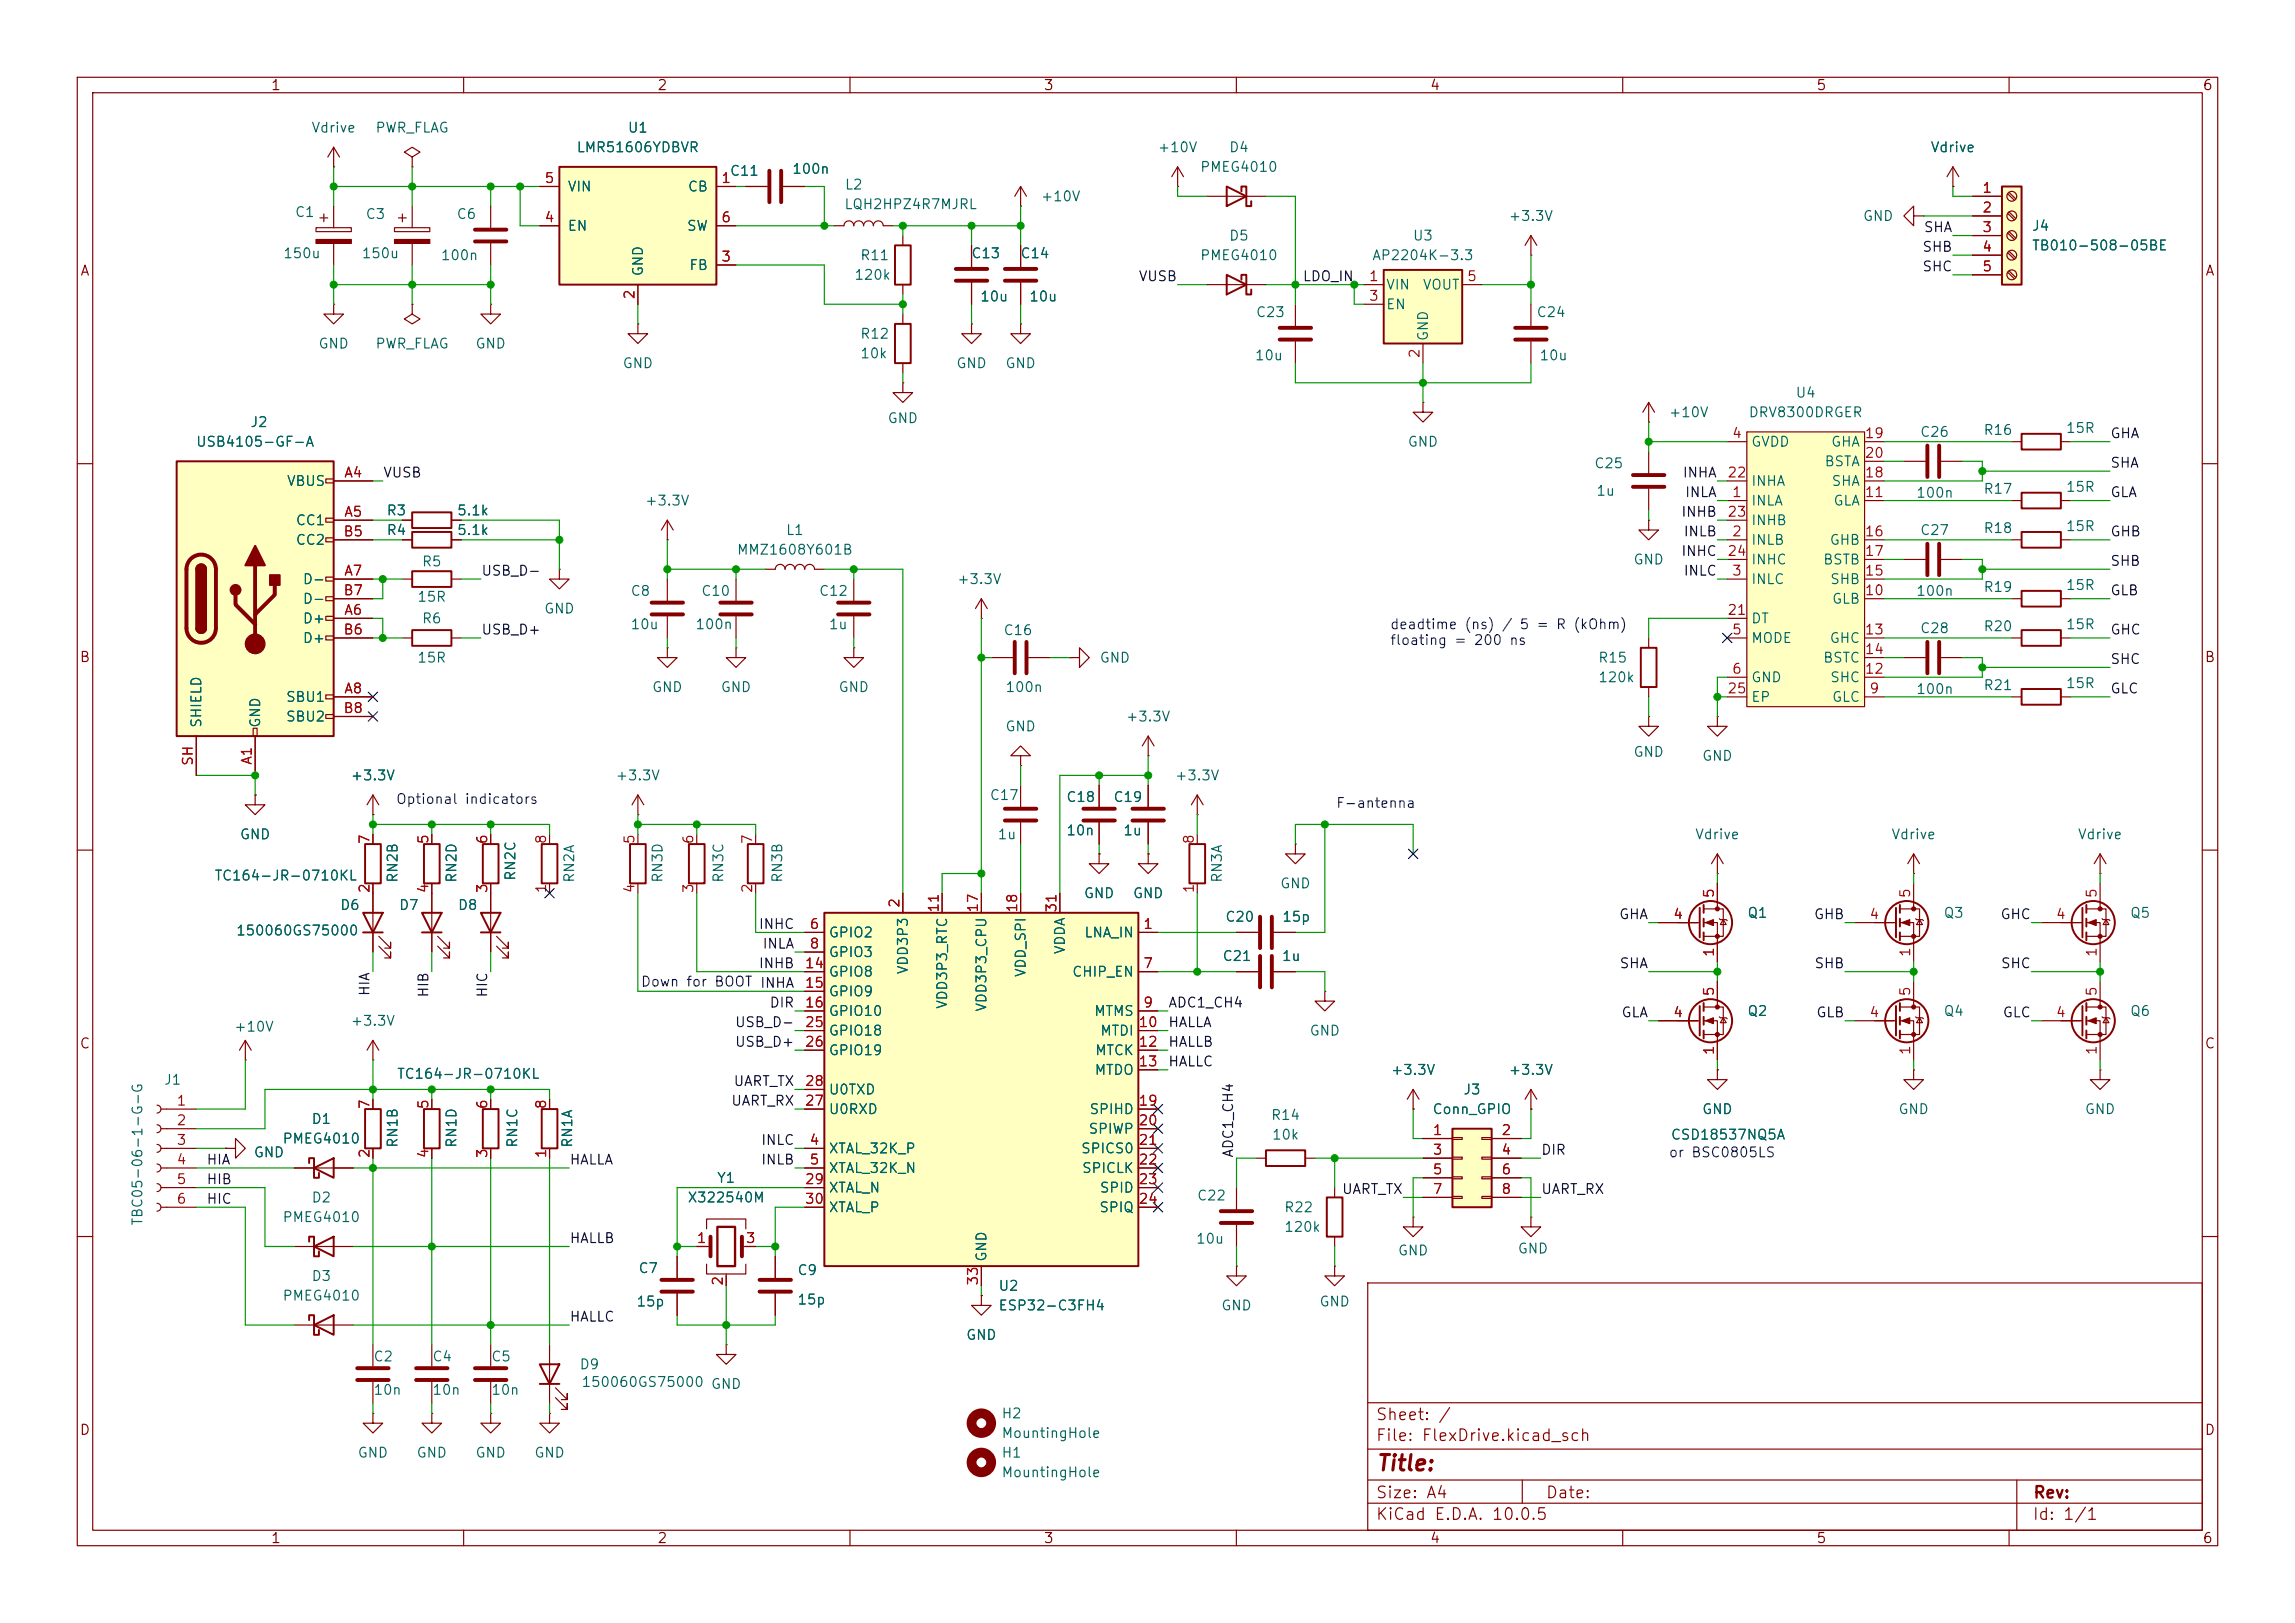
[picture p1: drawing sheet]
<svg xmlns="http://www.w3.org/2000/svg" width="297mm" height="210mm" viewBox="0 0 297 210" stroke-linecap="round" stroke-linejoin="round" font-family="sans-serif">
<defs><g id="words">
<text font-size="2" fill="#840000" x="178" y="190.8">Title:</text>
<g font-size="1.5" fill="#840000">
<text x="178" y="184.1">Sheet: /</text>
<text x="178" y="186.8">File: FlexDrive.kicad_sch</text>
<text x="178" y="197">KiCad E.D.A. 10.0.5</text>
<text x="178" y="194.2">Size: A4</text>
<text x="200" y="194.2">Date:</text>
<text x="263" y="197">Id: 1/1</text>
<text x="263" y="194.2">Rev:</text>
</g>
<g font-size="1.3" fill="#840000">
<text x="35" y="12">1</text>
<text x="85" y="12">2</text>
<text x="135" y="12">3</text>
<text x="185" y="12">4</text>
<text x="235" y="12">5</text>
<text x="285" y="12">6</text>
<text x="10.3" y="36">A</text>
<text x="285.3" y="36">A</text>
<text x="10.2" y="86">B</text>
<text x="285.2" y="86">B</text>
<text x="10.2" y="136">C</text>
<text x="285.2" y="136">C</text>
<text x="10.2" y="186">D</text>
<text x="285.2" y="186">D</text>
<text x="35" y="200">1</text>
<text x="85" y="200">2</text>
<text x="135" y="200">3</text>
<text x="185" y="200">4</text>
<text x="235" y="200">5</text>
<text x="285" y="200">6</text>
</g>
<g font-size="1.3" fill="#006464">
<text x="40.2" y="17.5">Vdrive</text>
<text x="48.5" y="17.5">PWR_FLAG</text>
<text x="81.2" y="17.5">U1</text>
<text x="74.5" y="20">LMR51606YDBVR</text>
<text x="94.4" y="23.1">C11</text>
<text x="102.4" y="22.8">100n</text>
<text x="149.7" y="20">+10V</text>
<text x="155.2" y="22.6">PMEG4010</text>
<text x="159" y="20">D4</text>
<text x="249.8" y="20">Vdrive</text>
<text x="38.1" y="28.4">C1</text>
<text x="47.2" y="28.6">C3</text>
<text x="59" y="28.6">C6</text>
<text x="73.4" y="25.1">VIN</text>
<text x="88.9" y="25.1">CB</text>
<text x="109.2" y="27.4">LQH2HPZ4R7MJRL</text>
<text x="109.2" y="24.8">L2</text>
<text x="134.6" y="26.4">+10V</text>
<text x="195.2" y="28.9">+3.3V</text>
<text x="241" y="28.9">GND</text>
<text x="36.6" y="33.7">150u</text>
<text x="46.7" y="33.7">150u</text>
<text x="57" y="34">100n</text>
<text x="73.4" y="30.2">EN</text>
<text x="83.5" y="35.8" transform="rotate(-90 83.5 35.8)">GND</text>
<text x="88.8" y="30.2">SW</text>
<text x="89.1" y="35.3">FB</text>
<text x="111.2" y="34">R11</text>
<text x="125.6" y="33.7">C13</text>
<text x="132" y="33.7">C14</text>
<text x="155.2" y="34">PMEG4010</text>
<text x="159" y="31.4">D5</text>
<text x="177.5" y="34">AP2204K-3.3</text>
<text x="182.8" y="31.4">U3</text>
<text x="262.9" y="30.2">J4</text>
<text x="262.9" y="32.7">TB010-508-05BE</text>
<text x="110.5" y="36.5">120k</text>
<text x="126.7" y="39.3">10u</text>
<text x="133.1" y="39.3">10u</text>
<text x="162.4" y="41.3">C23</text>
<text x="179.3" y="37.8">VIN</text>
<text x="179.3" y="40.3">EN</text>
<text x="184" y="37.8">VOUT</text>
<text x="198.8" y="41.3">C24</text>
<text x="41.1" y="45.4">GND</text>
<text x="48.5" y="45.4">PWR_FLAG</text>
<text x="61.4" y="45.4">GND</text>
<text x="80.5" y="48">GND</text>
<text x="111.2" y="44.1">R12</text>
<text x="111.2" y="46.7">10k</text>
<text x="123.7" y="48">GND</text>
<text x="130" y="48">GND</text>
<text x="162.3" y="46.9">10u</text>
<text x="185.1" y="44.2" transform="rotate(-90 185.1 44.2)">GND</text>
<text x="199.1" y="46.9">10u</text>
<text x="232.3" y="51.8">U4</text>
<text x="25.3" y="58.1">USB4105-GF-A</text>
<text x="32.3" y="55.6">J2</text>
<text x="114.8" y="55.1">GND</text>
<text x="182.1" y="58.1">GND</text>
<text x="215.9" y="54.3">+10V</text>
<text x="226.2" y="54.3">DRV8300DRGER</text>
<text x="226.5" y="58.1">GVDD</text>
<text x="236.9" y="58.1">GHA</text>
<text x="248.4" y="56.8">C26</text>
<text x="256.6" y="56.6">R16</text>
<text x="267.3" y="56.3">15R</text>
<text x="37" y="63.2">VBUS</text>
<text x="83.4" y="65.7">+3.3V</text>
<text x="206.2" y="60.9">C25</text>
<text x="206.5" y="64.5">1u</text>
<text x="226.5" y="65.7">INLA</text>
<text x="226.5" y="63.2">INHA</text>
<text x="236" y="60.7">BSTA</text>
<text x="236.9" y="63.2">SHA</text>
<text x="237.2" y="65.7">GLA</text>
<text x="247.9" y="64.7">100n</text>
<text x="256.6" y="64.2">R17</text>
<text x="267.3" y="64">15R</text>
<text x="38.2" y="68.3">CC1</text>
<text x="38.2" y="70.8">CC2</text>
<text x="49.9" y="69.5">R4</text>
<text x="49.9" y="67">R3</text>
<text x="59.1" y="69.5">5.1k</text>
<text x="59.1" y="67">5.1k</text>
<text x="101.6" y="69.5">L1</text>
<text x="226.5" y="70.8">INLB</text>
<text x="226.5" y="68.3">INHB</text>
<text x="236.7" y="70.8">GHB</text>
<text x="248.4" y="69.5">C27</text>
<text x="256.6" y="69.3">R18</text>
<text x="267.3" y="69">15R</text>
<text x="39.1" y="75.9">D-</text>
<text x="54.5" y="73.6">R5</text>
<text x="81.5" y="77.4">C8</text>
<text x="90.7" y="77.4">C10</text>
<text x="95.3" y="72.1">MMZ1608Y601B</text>
<text x="105.9" y="77.4">C12</text>
<text x="123.8" y="75.9">+3.3V</text>
<text x="211.3" y="73.4">GND</text>
<text x="226.5" y="75.9">INLC</text>
<text x="226.5" y="73.4">INHC</text>
<text x="235.8" y="73.4">BSTB</text>
<text x="236.8" y="75.9">SHB</text>
<text x="247.9" y="77.4">100n</text>
<text x="256.6" y="76.9">R19</text>
<text x="267.3" y="76.7">15R</text>
<text x="39.1" y="81">D+</text>
<text x="39.1" y="83.5">D+</text>
<text x="39.1" y="78.4">D-</text>
<text x="53.9" y="78.2">15R</text>
<text x="54.5" y="81">R6</text>
<text x="70.3" y="79.7">GND</text>
<text x="81.5" y="81.7">10u</text>
<text x="89.9" y="81.7">100n</text>
<text x="107.2" y="81.7">1u</text>
<text x="129.8" y="82.5">C16</text>
<text x="226.5" y="83.5">MODE</text>
<text x="226.5" y="81">DT</text>
<text x="236.7" y="83.5">GHC</text>
<text x="237" y="78.4">GLB</text>
<text x="248.4" y="82.2">C28</text>
<text x="256.6" y="82">R20</text>
<text x="267.3" y="81.7">15R</text>
<text x="53.9" y="86.1">15R</text>
<text x="84.3" y="89.9">GND</text>
<text x="93.2" y="89.9">GND</text>
<text x="108.4" y="89.9">GND</text>
<text x="130" y="89.9">100n</text>
<text x="142.2" y="86.1">GND</text>
<text x="206.7" y="86.1">R15</text>
<text x="206.7" y="88.6">120k</text>
<text x="226.5" y="88.6">GND</text>
<text x="235.8" y="86.1">BSTC</text>
<text x="236.8" y="88.6">SHC</text>
<text x="256.6" y="89.6">R21</text>
<text x="267.3" y="89.4">15R</text>
<text x="26.4" y="94.3" transform="rotate(-90 26.4 94.3)">SHIELD</text>
<text x="34" y="94.3" transform="rotate(-90 34 94.3)">GND</text>
<text x="36.9" y="91.1">SBU1</text>
<text x="36.9" y="93.7">SBU2</text>
<text x="130" y="94.9">GND</text>
<text x="145.6" y="93.7">+3.3V</text>
<text x="226.5" y="91.1">EP</text>
<text x="237" y="91.1">GLC</text>
<text x="247.9" y="90.1">100n</text>
<text x="45.3" y="101.3">+3.3V</text>
<text x="79.6" y="101.3">+3.3V</text>
<text x="152" y="101.3">+3.3V</text>
<text x="211.3" y="98.2">GND</text>
<text x="220.2" y="98.8">GND</text>
<text x="128" y="103.8">C17</text>
<text x="137.9" y="104.1">C18</text>
<text x="144" y="104.1">C19</text>
<text x="31" y="108.9">GND</text>
<text x="129" y="108.9">1u</text>
<text x="137.9" y="108.4">10n</text>
<text x="145.3" y="108.4">1u</text>
<text x="219.3" y="108.9">Vdrive</text>
<text x="244.7" y="108.9">Vdrive</text>
<text x="268.8" y="108.9">Vdrive</text>
<text x="27.7" y="114.2">TC164-JR-0710KL</text>
<text x="43.9" y="118.1">D6</text>
<text x="51.5" y="118.1">D7</text>
<text x="51.8" y="114.3" transform="rotate(-90 51.8 114.3)">RN2B</text>
<text x="59.2" y="118.1">D8</text>
<text x="59.4" y="114.3" transform="rotate(-90 59.4 114.3)">RN2D</text>
<text x="67" y="114.1" transform="rotate(-90 67 114.1)">RN2C</text>
<text x="74.6" y="114.3" transform="rotate(-90 74.6 114.3)">RN2A</text>
<text x="86.1" y="114.3" transform="rotate(-90 86.1 114.3)">RN3D</text>
<text x="93.9" y="114.3" transform="rotate(-90 93.9 114.3)">RN3C</text>
<text x="101.5" y="114.3" transform="rotate(-90 101.5 114.3)">RN3B</text>
<text x="140.2" y="116.5">GND</text>
<text x="146.5" y="116.5">GND</text>
<text x="158.4" y="114.3" transform="rotate(-90 158.4 114.3)">RN3A</text>
<text x="158.5" y="119.6">C20</text>
<text x="165.6" y="115.3">GND</text>
<text x="165.8" y="119.6">15p</text>
<text x="226" y="119.1">Q1</text>
<text x="251.4" y="119.1">Q3</text>
<text x="275.6" y="119.1">Q5</text>
<text x="30.5" y="121.4">150060GS75000</text>
<text x="107.2" y="121.6">GPIO2</text>
<text x="107.2" y="124.2">GPIO3</text>
<text x="138.1" y="123.6" transform="rotate(-90 138.1 123.6)">VDDA</text>
<text x="140.2" y="121.6">LNA_IN</text>
<text x="158.1" y="124.7">C21</text>
<text x="165.8" y="124.7">1u</text>
<text x="107.2" y="126.7">GPIO8</text>
<text x="107.2" y="129.2">GPIO9</text>
<text x="107.2" y="131.8">GPIO10</text>
<text x="117.8" y="126.2" transform="rotate(-90 117.8 126.2)">VDD3P3</text>
<text x="122.9" y="130.6" transform="rotate(-90 122.9 130.6)">VDD3P3_RTC</text>
<text x="128" y="131" transform="rotate(-90 128 131)">VDD3P3_CPU</text>
<text x="133" y="126.5" transform="rotate(-90 133 126.5)">VDD_SPI</text>
<text x="138.7" y="126.7">CHIP_EN</text>
<text x="141.5" y="131.8">MTMS</text>
<text x="226" y="131.8">Q2</text>
<text x="251.4" y="131.8">Q4</text>
<text x="275.6" y="131.8">Q6</text>
<text x="30.2" y="133.8">+10V</text>
<text x="45.3" y="133">+3.3V</text>
<text x="107.2" y="134.3">GPIO18</text>
<text x="107.2" y="136.9">GPIO19</text>
<text x="141.6" y="136.9">MTCK</text>
<text x="142.3" y="134.3">MTDI</text>
<text x="169.4" y="134.3">GND</text>
<text x="21.1" y="140.7">J1</text>
<text x="51.3" y="139.9">TC164-JR-0710KL</text>
<text x="107.2" y="141.9">U0TXD</text>
<text x="141.6" y="139.4">MTDO</text>
<text x="179.9" y="139.4">+3.3V</text>
<text x="189.3" y="141.9">J3</text>
<text x="195.2" y="139.4">+3.3V</text>
<text x="36.5" y="148.3">PMEG4010</text>
<text x="40.2" y="145.7">D1</text>
<text x="51.8" y="148.6" transform="rotate(-90 51.8 148.6)">RN1B</text>
<text x="59.4" y="148.6" transform="rotate(-90 59.4 148.6)">RN1D</text>
<text x="67.3" y="148.6" transform="rotate(-90 67.3 148.6)">RN1C</text>
<text x="74.4" y="148.6" transform="rotate(-90 74.4 148.6)">RN1A</text>
<text x="107.2" y="149.6">XTAL_32K_P</text>
<text x="107.2" y="144.5">U0RXD</text>
<text x="139.8" y="149.6">SPICS0</text>
<text x="140.8" y="147">SPIWP</text>
<text x="140.9" y="144.5">SPIHD</text>
<text x="164.4" y="145.2">R14</text>
<text x="164.5" y="147.8">10k</text>
<text x="185.3" y="144.5">Conn_GPIO</text>
<text x="216.1" y="147.8">CSD18537NQ5A</text>
<text x="220.2" y="144.5">GND</text>
<text x="245.6" y="144.5">GND</text>
<text x="269.7" y="144.5">GND</text>
<text x="32.8" y="150.1">GND</text>
<text x="40.2" y="155.9">D2</text>
<text x="88.9" y="155.9">X322540M</text>
<text x="92.7" y="153.4">Y1</text>
<text x="107.2" y="152.1">XTAL_32K_N</text>
<text x="107.2" y="154.6">XTAL_N</text>
<text x="139.9" y="152.1">SPICLK</text>
<text x="142.2" y="154.6">SPID</text>
<text x="154.8" y="155.6">C22</text>
<text x="18.7" y="158.7" transform="rotate(-90 18.7 158.7)">TBC05-06-1-G-G</text>
<text x="36.5" y="158.4">PMEG4010</text>
<text x="107.2" y="157.2">XTAL_P</text>
<text x="142.2" y="157.2">SPIQ</text>
<text x="154.7" y="161.2">10u</text>
<text x="166.1" y="157.2">R22</text>
<text x="166.1" y="159.7">120k</text>
<text x="40.2" y="166.1">D3</text>
<text x="82.5" y="165">C7</text>
<text x="103.1" y="165.3">C9</text>
<text x="128" y="163.3" transform="rotate(-90 128 163.3)">GND</text>
<text x="129.1" y="167.3">U2</text>
<text x="180.8" y="162.8">GND</text>
<text x="196.3" y="162.5">GND</text>
<text x="36.5" y="168.6">PMEG4010</text>
<text x="82.3" y="169.4">15p</text>
<text x="103.1" y="169.1">15p</text>
<text x="124.9" y="173.7">GND</text>
<text x="129.1" y="169.9">ESP32-C3FH4</text>
<text x="158" y="169.9">GND</text>
<text x="170.7" y="169.4">GND</text>
<text x="48.2" y="176.5">C2</text>
<text x="55.9" y="176.5">C4</text>
<text x="63.5" y="176.5">C5</text>
<text x="74.9" y="177.5">D9</text>
<text x="75.2" y="179.8">150060GS75000 GND</text>
<text x="48.2" y="180.8">10n</text>
<text x="55.9" y="180.8">10n</text>
<text x="63.5" y="180.8">10n</text>
<text x="129.5" y="183.8">H2</text>
<text x="46.2" y="188.9">GND</text>
<text x="53.8" y="188.9">GND</text>
<text x="61.4" y="188.9">GND</text>
<text x="69.1" y="188.9">GND</text>
<text x="129.5" y="188.9">H1</text>
<text x="129.5" y="191.5">MountingHole</text>
<text x="129.5" y="186.4">MountingHole</text>
</g>
<g font-size="1.3" fill="#a90000">
<text x="70.4" y="24">5</text>
<text x="93.2" y="24">1</text>
<text x="70.4" y="29.1">4</text>
<text x="93.2" y="29.1">6</text>
<text x="256.4" y="25.3">1</text>
<text x="256.4" y="27.8">2</text>
<text x="93.2" y="34.2">3</text>
<text x="256.4" y="30.3">3</text>
<text x="256.4" y="32.9">4</text>
<text x="256.4" y="35.4">5</text>
<text x="82.4" y="38.8" transform="rotate(-90 82.4 38.8)">2</text>
<text x="177.1" y="36.7">1</text>
<text x="177.1" y="39.2">3</text>
<text x="189.8" y="36.7">5</text>
<text x="184" y="46.5" transform="rotate(-90 184 46.5)">2</text>
<text x="224.1" y="57">4</text>
<text x="241.2" y="57">19</text>
<text x="241.2" y="59.6">20</text>
<text x="44.4" y="62.1">A4</text>
<text x="223.5" y="62.1">22</text>
<text x="224.1" y="64.6">1</text>
<text x="241.2" y="64.6">11</text>
<text x="241.2" y="62.1">18</text>
<text x="44.4" y="69.7">B5</text>
<text x="44.4" y="67.2">A5</text>
<text x="223.5" y="67.2">23</text>
<text x="224.1" y="69.7">2</text>
<text x="241.2" y="69.7">16</text>
<text x="44.4" y="77.3">B7</text>
<text x="44.4" y="74.8">A7</text>
<text x="223.5" y="72.3">24</text>
<text x="224.1" y="74.8">3</text>
<text x="241.2" y="77.3">10</text>
<text x="241.2" y="74.8">15</text>
<text x="241.2" y="72.3">17</text>
<text x="44.4" y="82.4">B6</text>
<text x="44.4" y="79.9">A6</text>
<text x="223.5" y="79.9">21</text>
<text x="224.1" y="82.4">5</text>
<text x="241.2" y="82.4">13</text>
<text x="224.1" y="87.5">6</text>
<text x="241.2" y="87.5">12</text>
<text x="241.2" y="85">14</text>
<text x="44.4" y="92.6">B8</text>
<text x="44.4" y="90">A8</text>
<text x="223.5" y="90">25</text>
<text x="241.8" y="90">9</text>
<text x="25.3" y="99.2" transform="rotate(-90 25.3 99.2)">SH</text>
<text x="32.9" y="99.1" transform="rotate(-90 32.9 99.1)">A1</text>
<text x="48.1" y="109.3" transform="rotate(-90 48.1 109.3)">7</text>
<text x="55.7" y="109.3" transform="rotate(-90 55.7 109.3)">5</text>
<text x="63.4" y="109.3" transform="rotate(-90 63.4 109.3)">6</text>
<text x="71" y="109.3" transform="rotate(-90 71 109.3)">8</text>
<text x="82.4" y="109.3" transform="rotate(-90 82.4 109.3)">5</text>
<text x="90" y="109.3" transform="rotate(-90 90 109.3)">6</text>
<text x="97.7" y="109.3" transform="rotate(-90 97.7 109.3)">7</text>
<text x="154.8" y="109.3" transform="rotate(-90 154.8 109.3)">8</text>
<text x="48.1" y="115.7" transform="rotate(-90 48.1 115.7)">2</text>
<text x="55.7" y="115.7" transform="rotate(-90 55.7 115.7)">4</text>
<text x="63.4" y="115.7" transform="rotate(-90 63.4 115.7)">3</text>
<text x="71" y="115.7" transform="rotate(-90 71 115.7)">1</text>
<text x="82.4" y="115.7" transform="rotate(-90 82.4 115.7)">4</text>
<text x="90" y="115.7" transform="rotate(-90 90 115.7)">3</text>
<text x="97.7" y="115.7" transform="rotate(-90 97.7 115.7)">2</text>
<text x="116.7" y="117.6" transform="rotate(-90 116.7 117.6)">2</text>
<text x="121.8" y="118.2" transform="rotate(-90 121.8 118.2)">11</text>
<text x="126.9" y="118.2" transform="rotate(-90 126.9 118.2)">17</text>
<text x="131.9" y="118.2" transform="rotate(-90 131.9 118.2)">18</text>
<text x="137" y="118.2" transform="rotate(-90 137 118.2)">31</text>
<text x="154.8" y="115.7" transform="rotate(-90 154.8 115.7)">1</text>
<text x="216.4" y="119.2">4</text>
<text x="222.1" y="116.3" transform="rotate(-90 222.1 116.3)">5</text>
<text x="241.8" y="119.2">4</text>
<text x="247.5" y="116.3" transform="rotate(-90 247.5 116.3)">5</text>
<text x="266" y="119.2">4</text>
<text x="271.6" y="116.3" transform="rotate(-90 271.6 116.3)">5</text>
<text x="104.1" y="125.6">14</text>
<text x="104.7" y="120.5">6</text>
<text x="104.7" y="123.1">8</text>
<text x="147.9" y="120.5">1</text>
<text x="147.9" y="125.6">7</text>
<text x="222.1" y="123.9" transform="rotate(-90 222.1 123.9)">1</text>
<text x="247.5" y="123.9" transform="rotate(-90 247.5 123.9)">1</text>
<text x="271.6" y="123.9" transform="rotate(-90 271.6 123.9)">1</text>
<text x="104.1" y="128.1">15</text>
<text x="104.1" y="130.7">16</text>
<text x="147.9" y="130.7">9</text>
<text x="216.4" y="131.9">4</text>
<text x="222.1" y="129" transform="rotate(-90 222.1 129)">5</text>
<text x="241.8" y="131.9">4</text>
<text x="247.5" y="129" transform="rotate(-90 247.5 129)">5</text>
<text x="266" y="131.9">4</text>
<text x="271.6" y="129" transform="rotate(-90 271.6 129)">5</text>
<text x="104.1" y="133.2">25</text>
<text x="104.1" y="135.8">26</text>
<text x="147.3" y="133.2">10</text>
<text x="147.3" y="135.8">12</text>
<text x="222.1" y="136.6" transform="rotate(-90 222.1 136.6)">1</text>
<text x="247.5" y="136.6" transform="rotate(-90 247.5 136.6)">1</text>
<text x="271.6" y="136.6" transform="rotate(-90 271.6 136.6)">1</text>
<text x="22.8" y="143.4">1</text>
<text x="48.1" y="143.6" transform="rotate(-90 48.1 143.6)">7</text>
<text x="55.7" y="143.6" transform="rotate(-90 55.7 143.6)">5</text>
<text x="63.4" y="143.6" transform="rotate(-90 63.4 143.6)">6</text>
<text x="71" y="143.6" transform="rotate(-90 71 143.6)">8</text>
<text x="104.1" y="143.4">27</text>
<text x="104.1" y="140.8">28</text>
<text x="147.3" y="138.3">13</text>
<text x="147.3" y="143.4">19</text>
<text x="22.8" y="145.9">2</text>
<text x="22.8" y="148.5">3</text>
<text x="48.1" y="150" transform="rotate(-90 48.1 150)">2</text>
<text x="55.7" y="150" transform="rotate(-90 55.7 150)">4</text>
<text x="63.4" y="150" transform="rotate(-90 63.4 150)">3</text>
<text x="71" y="150" transform="rotate(-90 71 150)">1</text>
<text x="104.7" y="148.5">4</text>
<text x="147.3" y="145.9">20</text>
<text x="147.3" y="148.5">21</text>
<text x="185.3" y="147.2">1</text>
<text x="185.3" y="149.7">3</text>
<text x="194.2" y="147.2">2</text>
<text x="194.2" y="149.7">4</text>
<text x="22.8" y="151">4</text>
<text x="22.8" y="153.5">5</text>
<text x="104.1" y="153.5">29</text>
<text x="104.7" y="151">5</text>
<text x="147.3" y="151">22</text>
<text x="147.3" y="153.5">23</text>
<text x="185.3" y="152.3">5</text>
<text x="185.3" y="154.8">7</text>
<text x="194.2" y="152.3">6</text>
<text x="194.2" y="154.8">8</text>
<text x="22.8" y="156.1">6</text>
<text x="90.1" y="161.2">1</text>
<text x="96.4" y="161.2">3</text>
<text x="104.1" y="156.1">30</text>
<text x="147.3" y="156.1">24</text>
<text x="93.8" y="166.5" transform="rotate(-90 93.8 166.5)">2</text>
<text x="126.9" y="166.4" transform="rotate(-90 126.9 166.4)">33</text>
</g>
<g font-size="1.3" fill="#0f0f0f">
<text x="248.7" y="32.9">SHB</text>
<text x="248.7" y="35.4">SHC</text>
<text x="248.9" y="30.4">SHA</text>
<text x="147.3" y="36.7">VUSB</text>
<text x="168.5" y="36.7">LDO_IN</text>
<text x="273" y="57">GHA</text>
<text x="49.5" y="62.1">VUSB</text>
<text x="217.7" y="62.1">INHA</text>
<text x="218" y="64.6">INLA</text>
<text x="273" y="60.8">SHA</text>
<text x="273" y="64.6">GLA</text>
<text x="217.5" y="67.2">INHB</text>
<text x="217.8" y="69.7">INLB</text>
<text x="273" y="69.7">GHB</text>
<text x="62.2" y="74.8">USB_D-</text>
<text x="217.5" y="72.3">INHC</text>
<text x="217.8" y="74.8">INLC</text>
<text x="273" y="77.3">GLB</text>
<text x="273" y="73.5">SHB</text>
<text x="62.2" y="82.4">USB_D+</text>
<text x="273" y="82.4">GHC</text>
<text x="273" y="86.2">SHC</text>
<text x="273" y="90">GLC</text>
<text x="209.4" y="119.3">GHA</text>
<text x="234.7" y="119.3">GHB</text>
<text x="258.8" y="119.3">GHC</text>
<text x="98.1" y="125.6">INHB</text>
<text x="98.1" y="120.5">INHC</text>
<text x="98.6" y="123.1">INLA</text>
<text x="209.5" y="125.6">SHA</text>
<text x="234.7" y="125.6">SHB</text>
<text x="258.9" y="125.6">SHC</text>
<text x="48.1" y="129" transform="rotate(-90 48.1 129)">HIA</text>
<text x="55.8" y="129.2" transform="rotate(-90 55.8 129.2)">HIB</text>
<text x="63.4" y="129.2" transform="rotate(-90 63.4 129.2)">HIC</text>
<text x="99.5" y="130.7">DIR</text>
<text x="151.1" y="130.7">ADC1_CH4</text>
<text x="209.7" y="132">GLA</text>
<text x="235" y="132">GLB</text>
<text x="259.1" y="132">GLC</text>
<text x="95" y="133.2">USB_D-</text>
<text x="95" y="135.8">USB_D+</text>
<text x="151.1" y="133.2">HALLA</text>
<text x="151.1" y="135.8">HALLB</text>
<text x="94.5" y="143.4">UART_RX</text>
<text x="94.8" y="140.8">UART_TX</text>
<text x="151.1" y="138.3">HALLC</text>
<text x="98.4" y="148.5">INLC</text>
<text x="159.9" y="149.9" transform="rotate(-90 159.9 149.9)">ADC1_CH4</text>
<text x="199.4" y="149.7">DIR</text>
<text x="26.6" y="153.5">HIB</text>
<text x="26.6" y="151">HIA</text>
<text x="73.6" y="151">HALLA</text>
<text x="98.4" y="151">INLB</text>
<text x="173.6" y="154.8">UART_TX</text>
<text x="199.4" y="154.8">UART_RX</text>
<text x="26.6" y="156.1">HIC</text>
<text x="73.6" y="161.2">HALLB</text>
<text x="73.6" y="171.3">HALLC</text>
</g>
<g font-size="1.3" fill="#0000c2">
<text x="179.8" y="81.7">deadtime (ns) / 5 = R (kOhm)</text>
<text x="179.8" y="83.8">floating = 200 ns</text>
<text x="51.2" y="104.3">Optional indicators</text>
<text x="172.8" y="104.9">F-antenna</text>
<text x="82.8" y="128">Down for BOOT INHA</text>
<text x="215.9" y="150.1">or BSC0805LS</text>
</g>
</g></defs>
<g fill="none" stroke="#840000" stroke-width=".15">
<path d="M10 10h277v190h-277zM12 12h273v186h-273zM60 10v2M110 10v2M160 10v2M210 10v2M260 10v2M246.4 59.7h2.8M251.2 59.7h2.8M10 60h2M285 60h2M213.4 92.7v1.3h1.2l-1.2 1.3-1.3-1.3h1.3"/>
<path d="M213.4 92.7h.1M213.4 82.6v1.2M213.4 88.9v1.3M222.2 92.7v1.3h1.3l-1.3 1.3-1.2-1.3h1.2M222.2 92.7h.1M246.4 85.1h2.8M251.2 85.1h2.8M10 110h2M222.2 113h.1M222.2 110.5l-.7 1.3M222.2 110.5l.8 1.3M222.2 110.5v2.5"/>
<path d="M240 119.4h5.4M245.9 117.6h2.5v3.6h-2.5M245.9 119.4h1.7v5.1M247.6 114.3v3.3M247.9 118.9l.1 .1h.8l.1 .1M248.4 119l.4 .6h-.8zM285 110h2M247.6 138.4v1.3h1.3l-1.3 1.3-1.2-1.3h1.2M247.6 138.4h.1M271.8 138.4v1.3h1.2l-1.2 1.3-1.3-1.3h1.3M271.8 138.4h.1M29.2 148.6h1.3v-1.3l1.2 1.3-1.2 1.3v-1.3"/>
<path d="M29.2 148.6h.1M38.1 151.1h7.6M10 160h2M38.1 161.3h7.6M38.1 171.5h7.6M177 166h108v32h-108zM285 160h2M60 198v2M110 198v2M160 198v2M177 194.5h108M177 191.5h108"/>
<path d="M177 187.5h108M177 181.5h108M197 191.5v3M210 198v2M260 198v2M261 191.5v6.5"/>
</g>
<g fill="none" stroke="#840000" stroke-width=".25">
<path d="M212.3 83.8h2.1v5.1h-2.1zM245.4 117.5v3.8M245.9 117.1v1M245.9 118.9v1M245.9 120.7v1M40 150.5v-.6h.6v2.5h.7v-.6M40.6 151.1l2.6-1.2v2.5zM40 160.7v-.7h.6v2.6h.7v-.7M40 170.8v-.6h.6v2.5h.7v-.6M40.6 161.3l2.6-1.3v2.6zM40.6 171.5l2.6-1.3v2.5z"/>
<circle cx="246.8" cy="119.4" r="2.79"/>
</g>
<g fill="#840000" stroke="#840000" stroke-width=".15">
<path d="M246.1 119.4l1-.4v.8z"/>
<circle cx="247.6" cy="117.6" r=".25"/>
<circle cx="247.6" cy="121.2" r=".25"/>
</g>
<path d="M249.4 57.7v4M251 57.7v4M249.4 83.1v4M251 83.1v4" fill="none" stroke="#840000" stroke-width=".51"/>
<path d="M226.1 55.9h15.2v35.5h-15.2z" fill="#ffffc2"/>
<g fill="none" stroke="#840000" stroke-width=".15">
<path d="M223.5 57.2h2.6M226.1 55.9h15.2v35.5h-15.2zM241.3 57.2h2.5M241.3 59.7h2.5M223.5 64.8h2.6M223.5 69.9h2.6M223.5 74.9h2.6M223.5 72.4h2.6M223.5 62.2h2.6M223.5 67.3h2.6M241.3 64.8h2.5M241.3 69.9h2.5"/>
<path d="M241.3 74.9h2.5M241.3 77.5h2.5M241.3 72.4h2.5M241.3 62.2h2.5M246.4 72.4h2.8M251.2 72.4h2.8M260.3 69.9h1.3M266.7 69.9h1.3M223.5 82.6h2.6M223.5 87.6h2.6M223.5 90.2h2.6M223.5 80h2.6"/>
<path d="M241.3 82.6h2.5M241.3 87.6h2.5M241.3 90.2h2.5M241.3 85.1h2.5M264.2 132.1h5.3M270 130.3h2.5v3.6h-2.5M270 132.1h1.8v5.1M271.8 127v3.3M272 131.6l.2 .1h.7l.1 .1M272.5 131.7l.4 .6h-.7zM48.3 142.2v1.3M48.3 148.6v1.3"/>
<path d="M127 167.6v1.3h1.3l-1.3 1.3-1.3-1.3h1.3M127 167.6h.1"/>
</g>
<path d="M249.4 70.4v4M251 70.4v4" fill="none" stroke="#840000" stroke-width=".51"/>
<g fill="none" stroke="#840000" stroke-width=".25">
<path d="M261.6 68.8h5.1v2.1h-5.1zM269.5 130.2v3.8M270 129.8v1M270 131.6v1M270 133.4v1M47.2 143.5h2.1v5.1h-2.1z"/>
<circle cx="270.9" cy="132.1" r="2.79"/>
</g>
<g fill="none" stroke="#840000" stroke-width="1.3">
<circle cx="127" cy="189.2" r="1.27"/>
<circle cx="127" cy="184.1" r="1.27"/>
</g>
<g fill="#840000" stroke="#840000" stroke-width=".15">
<path d="M270.3 132.1l1-.4v.8z"/>
<circle cx="271.8" cy="130.3" r=".25"/>
<circle cx="271.8" cy="133.9" r=".25"/>
</g>
<path d="M106.7 118.1h40.6v45.7h-40.6z" fill="#ffffc2"/>
<g fill="none" stroke="#840000" stroke-width=".25">
<path d="M261.6 63.8h5.1v2h-5.1zM106.7 118.1h40.6v45.7h-40.6zM269.5 117.5v3.8M270 117.1v1M270 118.9v1M245.4 130.2v3.8M245.9 129.8v1M245.9 131.6v1M245.9 133.4v1M270 120.7v1"/>
<circle cx="270.9" cy="119.4" r="2.79"/>
<circle cx="246.8" cy="132.1" r="2.79"/>
</g>
<g fill="none" stroke="#840000" stroke-width=".15">
<path d="M260.3 64.8h1.3M266.7 64.8h1.3M116.8 115.6v2.5M121.9 115.6v2.5M127 115.6v2.5M132.1 115.6v2.5M137.2 115.6v2.5M264.2 119.4h5.3M270 117.6h2.5v3.6h-2.5M270 119.4h1.8v5.1M271.8 113h.1M271.8 110.5l-.8 1.3"/>
<path d="M271.8 110.5l.7 1.3M271.8 110.5v2.5M271.8 114.3v3.3M272 118.9l.2 .1h.7l.1 .1M272.5 119l.4 .6h-.7zM104.1 120.7h2.6M104.1 125.7h2.6M104.1 123.2h2.6M104.1 130.8h2.6M104.1 133.4h2.6M104.1 135.9h2.6M104.1 128.3h2.6"/>
<path d="M147.3 120.7h2.6M147.3 125.7h2.6M147.3 130.8h2.6M147.3 133.4h2.6M147.3 135.9h2.6M147.3 138.4h2.6M240 132.1h5.4M245.9 130.3h2.5v3.6h-2.5M245.9 132.1h1.7v5.1M247.6 127v3.3M247.9 131.6l.1 .1h.8l.1 .1M248.4 131.7l.4 .6h-.8z"/>
<path d="M104.1 148.6h2.6M104.1 151.1h2.6M104.1 143.5h2.6M104.1 153.7h2.6M104.1 156.2h2.6M104.1 141h2.6M147.3 148.6h2.6M147.3 151.1h2.6M147.3 143.5h2.6M147.3 146.1h2.6M147.3 153.7h2.6M147.3 156.2h2.6"/>
<path d="M127 163.8v2.6"/>
</g>
<g fill="#840000" stroke="#840000" stroke-width=".15">
<path d="M246.1 132.1l1-.4v.8z"/>
<path d="M270.3 119.4l1-.4v.8z"/>
<circle cx="247.6" cy="130.3" r=".25"/>
<circle cx="247.6" cy="133.9" r=".25"/>
<circle cx="271.8" cy="117.6" r=".25"/>
<circle cx="271.8" cy="121.2" r=".25"/>
</g>
<path d="M22.9 59.7h20.3v35.6h-20.3z" fill="#ffffc2"/>
<g fill="none" stroke="#840000" stroke-width=".15">
<path d="M247.6 27.9v-1.2l-1.2 1.2 1.2 1.3v-1.3h1.3M248.9 27.9h.1M252.7 24.1h.1M252.7 21.6l-.7 1.3M252.7 21.6l.8 1.3M252.7 21.6v2.5M184.1 52.1v1.2h1.3l-1.3 1.3-1.2-1.3h1.2M184.1 52.1h.1M213.4 54.6h.1M213.4 52.1l-.8 1.2M213.4 52.1l.7 1.2M213.4 52.1v2.5"/>
<path d="M213.4 58.4v2.8M260.3 57.2h1.3M266.7 57.2h1.3M42.2 62h1v.5h-1zM42.2 67.1h1v.5h-1zM42.2 69.6h1v.5h-1zM42.2 74.7h1v.5h-1zM42.2 77.2h1v.5h-1zM42.2 79.8h1v.5h-1zM43.2 62.2h5.1M43.2 67.3h5.1M43.2 74.9h5.1"/>
<path d="M43.2 69.9h5.1M43.2 77.5h5.1M52.1 67.3h1.2M52.1 74.9h1.2M52.1 69.9h1.2M58.4 67.3h1.3M58.4 74.9h1.3M58.4 69.9h1.3M213.4 67.3v1.3h1.2l-1.2 1.3-1.3-1.3h1.3M213.4 67.3h.1M213.4 63.2v2.8M260.3 77.5h1.3"/>
<path d="M266.7 77.5h1.3M25.4 95.3v5M32.8 94.2h.5v1.1h-.5zM33 95.3v5M42.2 82.3h1v.5h-1zM42.2 89.9h1v.5h-1zM42.2 92.5h1v.5h-1zM43.2 80h5.1M43.2 90.2h5.1M43.2 82.6h5.1M43.2 92.7h5.1M52.1 82.6h1.2"/>
<path d="M58.4 82.6h1.3M260.3 90.2h1.3M260.3 82.6h1.3M266.7 90.2h1.3M266.7 82.6h1.3M33 102.9v1.2h1.3l-1.3 1.3-1.3-1.3h1.3M33 102.9h.1M48.3 105.4h.1M48.3 102.9l-.8 1.2M48.3 102.9l.7 1.2M48.3 102.9v2.5M48.3 108v1.2"/>
<path d="M48.3 114.3v8.9M55.9 108v1.2M55.9 114.3v8.9M63.5 108v1.2M63.5 114.3v8.9M71.1 108v1.2M71.1 114.3v1.3M82.5 105.4h.1M82.5 102.9v2.5M82.5 108v1.2M82.5 114.3v1.3M82.5 102.9l-.7 1.2"/>
<path d="M82.5 102.9l.8 1.2M132.1 101.6v2.8M132.1 106.4v2.8M148.6 110.5v1.3h1.3l-1.3 1.2-1.3-1.2h1.3M148.6 110.5h.1M154.9 108v1.2M154.9 114.3v1.3M31.7 137.2h.1M31.7 134.6l-.7 1.3M31.7 134.6l.8 1.3M31.7 134.6v2.6M48.3 137.2h.1"/>
<path d="M48.3 134.6v2.6M48.3 134.6l-.8 1.3M48.3 134.6l.7 1.3M49 122.4l1.5 1.6v-.8v.8h-.7M49 121.2l1.5 1.5v-.8v.8h-.7M56.6 122.4l1.6 1.6v-.8v.8h-.8M56.6 121.2l1.6 1.5v-.8v.8h-.8M64.3 122.4l1.5 1.6v-.8v.8h-.8M64.3 121.2l1.5 1.5v-.8v.8h-.8M71.1 142.2v1.3M71.1 148.6v1.3M91.4 159v-1.3h5.1v1.3"/>
<path d="M90.2 161.3h1.7M91.4 163.6v1.2h5.1v-1.2M94 174v1.3h1.2l-1.2 1.2-1.3-1.2h1.3M94 174h.1M94 164.8v1.6M96 161.3h1.8M100.3 162.6v2.8M100.3 167.4v2.8"/>
</g>
<g fill="none" stroke="#840000" stroke-width=".25">
<path d="M22.9 59.7h20.3v35.6h-20.3zM261.6 56.1h5.1v2.1h-5.1zM25.4 73.7a.64 .64 0 0 1 .6-.7 .64 .64 0 0 1 .7 .7M53.3 68.8h5.1v2.1h-5.1zM53.3 66.3h5.1v2h-5.1zM53.3 73.9h5.1v2h-5.1zM261.6 76.5h5.1v2h-5.1zM25.4 81.3a.64 .64 0 0 0 .6 .6 .64 .64 0 0 0 .7-.6M53.3 81.5h5.1v2.1h-5.1zM261.6 89.2h5.1v2h-5.1zM261.6 81.5h5.1v2.1h-5.1zM47 118.1h2.5l-1.2 2.6z"/>
<path d="M47.2 109.2h2.1v5.1h-2.1zM54.6 118.1h2.5l-1.2 2.6zM54.9 109.2h2v5.1h-2zM62.2 118.1h2.6l-1.3 2.6zM62.5 109.2h2v5.1h-2zM70.1 109.2h2v5.1h-2zM81.5 109.2h2.1v5.1h-2.1zM153.9 109.2h2.1v5.1h-2.1zM47 120.7h2.5M54.6 120.7h2.5M62.2 120.7h2.6M70.1 143.5h2v5.1h-2z"/>
</g>
<path d="M24.7 72.3a1.9 1.9 0 0 1 2.1-.4 1.9 1.9 0 0 1 1.1 1.8v7.6a1.91 1.91 0 0 1-1.9 1.9 1.91 1.91 0 0 1-1.9-1.9v-7.6a1.9 1.9 0 0 1 .6-1.4zM30.5 77v1.2l2.5 2.6M33 73.2v10.1M35.6 75.7v1.3l-2.6 2.5M211.3 61.5h4.1M211.3 63h4.1M130 104.6h4.1M130 106.2h4.1M91.9 160v2.6M96 160v2.6M98.3 165.6h4.1M98.3 167.1h4.1" fill="none" stroke="#840000" stroke-width=".51"/>
<g fill="#840000" stroke="#840000" stroke-width=".25">
<path d="M25.4 73.7h1.3v7.6h-1.3z"/>
<path d="M25.6 73.2a.64 .64 0 0 1 .7-.1 .64 .64 0 0 1 .4 .6h-1.3z"/>
<path d="M25.4 81.3h1.3a.64 .64 0 0 1-.7 .6 .64 .64 0 0 1-.6-.6z"/>
<path d="M33 70.6l1.3 2.6h-2.6z"/>
<path d="M34.9 74.4h1.3v1.3h-1.3z"/>
<circle cx="30.5" cy="76.3" r=".63"/>
</g>
<circle cx="33" cy="83.3" r="1.27" fill="#840000" stroke="#840000" stroke-width=".15"/>
<path d="M92.8 158.8h2.3v5h-2.3z" fill="none" stroke="#840000" stroke-width=".3"/>
<path d="M259.1 24.1h2.5v12.7h-2.5z" fill="#ffffc2"/>
<g fill="none" stroke="#840000" stroke-width=".25">
<path d="M158.7 35.6l2.6 1.2-2.6 1.3zM160.7 36.2v-.6h.6v2.5h.6v-.6M259.1 24.1h2.5v12.7h-2.5zM89.2 109.2h2v5.1h-2zM96.8 109.2h2v5.1h-2zM220 117.5v3.8M220.5 117.1v1M220.5 118.9v1M220 130.2v3.8M220.5 120.7v1M220.5 129.8v1M220.5 131.6v1"/>
<path d="M220.5 133.4v1M54.9 143.5h2v5.1h-2zM62.5 143.5h2v5.1h-2zM163.8 148.8h5.1v2.1h-5.1zM69.8 176.5h2.6l-1.3 2.6zM69.8 179.1h2.6"/>
<circle cx="221.4" cy="119.4" r="2.79"/>
<circle cx="221.4" cy="132.1" r="2.79"/>
</g>
<g fill="none" stroke="#840000" stroke-width=".15">
<path d="M40.9 29.5h4.6v.5h-4.6zM41.4 28.2h1M41.9 27.7v1M43.2 26.7v2.8M43.2 31.5v2.8M51.1 29.5h4.5v.5h-4.5zM51.6 28.2h1M52.1 27.7v1M53.3 26.7v2.8M53.3 31.5v2.8M63.5 39.4v1.2h1.3l-1.3 1.3-1.3-1.3h1.3M63.5 39.4h.1"/>
<path d="M63.5 26.7v2.8M63.5 31.5v2.8M156.2 36.8h7.6M167.6 39.4v2.8M255.3 25.4h3.8M255.3 27.9h3.8M255.3 30.5h3.8M255.3 33h3.8M255.3 35.6h3.8M259.8 25.1l.9 .8M259.8 27.6l.9 .8M259.8 30.1l.9 .9"/>
<path d="M259.8 32.7l.9 .8M259.8 35.2l.9 .9M260 24.9l.9 .8M260 27.4l.9 .9M260 30l.9 .8M260 32.5l.9 .9M260 35.1l.9 .8M167.6 44.2v2.8M127 77.5l-.8 1.2M127 77.5l.8 1.2M127 77.5v2.5M127 80h.1"/>
<path d="M128.3 85.1h2.8M132.1 97.8h1.2l-1.2-1.3-1.3 1.3h1.3v1.3M132.1 99.1h.1M133.1 85.1h2.8M138.4 85.1h1.3v-1.3l1.3 1.3-1.3 1.3v-1.3M138.4 85.1h.1M148.6 97.8h.1M148.6 95.3l-.8 1.2M148.6 95.3l.8 1.2M148.6 95.3v2.5M90.2 108v1.2M90.2 114.3v1.3"/>
<path d="M97.8 108v1.2M97.8 114.3v1.3M142.2 110.5v1.3h1.3l-1.3 1.2-1.2-1.2h1.2M142.2 110.5h.1M142.2 101.6v2.8M142.2 106.4v2.8M148.6 101.6v2.8M148.6 106.4v2.8M154.9 105.4h.1M154.9 102.9l-.7 1.2M154.9 102.9l.8 1.2M154.9 102.9v2.5"/>
<path d="M167.6 109.2v1.3h1.3l-1.3 1.3-1.2-1.3h1.2M167.6 109.2h.1M214.6 119.4h5.4M220.5 117.6h2.5v3.6h-2.5M220.5 119.4h1.7v5.1M222.2 114.3v3.3M222.5 118.9l.1 .1h.8l.1 .1M223 119l.4 .6h-.8zM214.6 132.1h5.4M220.5 130.3h2.5v3.6h-2.5M220.5 132.1h1.7v5.1M222.2 138.4v1.3h1.3l-1.3 1.3-1.2-1.3h1.2"/>
<path d="M222.2 138.4h.1M222.2 127v3.3M222.5 131.6l.1 .1h.8l.1 .1M223 131.7l.4 .6h-.8zM20.3 143a.51 .51 0 0 1 .5 .5 .51 .51 0 0 1-.5 .5M20.3 145.5a.51 .51 0 0 1 .5 .6 .51 .51 0 0 1-.5 .5M20.3 148.1a.51 .51 0 0 1 .5 .5 .51 .51 0 0 1-.5 .5M20.3 150.6a.51 .51 0 0 1 .5 .5 .51 .51 0 0 1-.5 .5M20.3 153.2a.51 .51 0 0 1 .5 .5 .51 .51 0 0 1-.5 .5M20.3 155.7a.51 .51 0 0 1 .5 .5 .51 .51 0 0 1-.5 .5M20.8 143.5h4.6M20.8 146.1h4.6"/>
<path d="M20.8 148.6h4.6M20.8 151.1h4.6M20.8 153.7h4.6M20.8 156.2h4.6M55.9 142.2v1.3M55.9 148.6v1.3M63.5 142.2v1.3M63.5 148.6v1.3M162.6 149.9h1.2M168.9 149.9h1.3M198.1 143.5h.1M198.1 141l-.7 1.2"/>
<path d="M198.1 141l.8 1.2M198.1 141v2.5M48.3 174v2.8M48.3 178.8v2.8M55.9 174v2.8M55.9 178.8v2.8M63.5 174v2.8M63.5 178.8v2.8M71.1 174v7.6M71.9 179.6l1.5 1.5v-.8v.8h-.8M87.6 162.6v2.8M87.6 167.4v2.8"/>
<path d="M48.3 182.9v1.3h1.2l-1.2 1.2-1.3-1.2h1.3M48.3 182.9h.1M55.9 182.9v1.3h1.2l-1.2 1.2-1.3-1.2h1.3M55.9 182.9h.1M63.5 182.9v1.3h1.3l-1.3 1.2-1.3-1.2h1.3M63.5 182.9h.1M71.1 182.9v1.3h1.3l-1.3 1.2-1.3-1.2h1.3M71.1 182.9h.1M71.9 180.8l1.5 1.6v-.8v.8h-.8"/>
<circle cx="260.3" cy="30.5" r=".63"/>
<circle cx="260.3" cy="27.9" r=".63"/>
<circle cx="260.3" cy="33" r=".63"/>
<circle cx="260.3" cy="35.6" r=".63"/>
<circle cx="260.3" cy="25.4" r=".63"/>
</g>
<g fill="none" stroke="#840000" stroke-width=".51">
<path d="M61.5 31.2h4M61.5 29.7h4M165.6 43.9h4.1M165.6 42.4h4.1M131.3 83.1v4M132.8 83.1v4M140.2 104.6h4.1M140.2 106.2h4.1M146.6 104.6h4M146.6 106.2h4M46.2 177h4.1M46.2 178.6h4.1"/>
<path d="M53.8 177h4.1M53.8 178.6h4.1M61.5 177h4M61.5 178.6h4M85.6 165.6h4.1M85.6 167.1h4.1"/>
</g>
<g fill="#840000" stroke="#840000" stroke-width=".15">
<path d="M220.7 119.4l1-.4v.8z"/>
<path d="M220.7 132.1l1-.4v.8z"/>
<path d="M51.1 31h4.5v.5h-4.5z"/>
<path d="M40.9 31h4.6v.5h-4.6z"/>
<circle cx="222.2" cy="117.6" r=".25"/>
<circle cx="222.2" cy="121.2" r=".25"/>
<circle cx="222.2" cy="130.3" r=".25"/>
<circle cx="222.2" cy="133.9" r=".25"/>
</g>
<path d="M72.4 21.6h20.3v15.2h-20.3z" fill="#ffffc2"/>
<path d="M72.4 21.6h20.3v15.2h-20.3zM171.7 154.9h2v5.1h-2z" fill="none" stroke="#840000" stroke-width=".25"/>
<g fill="none" stroke="#840000" stroke-width=".15">
<path d="M43.2 19.1l-.8 1.2M43.2 19.1l.7 1.2M43.2 19.1v2.5M43.2 21.6h.1M43.2 39.4v1.2h1.2l-1.2 1.3-1.3-1.3h1.3M43.2 39.4h.1M53.3 20.3l1.1-.6-1.1-.6-1 .6 1 .6v1.3M53.3 21.6h.1M69.8 24.1h2.6M69.8 29.2h2.6M82.5 36.8v2.6M92.7 24.1h2.5"/>
<path d="M92.7 34.3h2.5M92.7 29.2h2.5M82.5 41.9v1.3h1.3l-1.3 1.3-1.2-1.3h1.2M82.5 41.9h.1M116.8 49.5v1.3h1.3l-1.3 1.3-1.2-1.3h1.2M116.8 49.5h.1M72.4 73.7v1.2h1.3l-1.3 1.3-1.3-1.3h1.3M72.4 73.7h.1M86.4 69.9h.1M86.4 67.3v2.6M86.4 74.9v2.8M86.4 79.8v2.8"/>
<path d="M86.4 67.3l-.8 1.3M86.4 67.3l.7 1.3M95.2 74.9v2.8M95.2 79.8v2.8M99.1 73.7h1.2a.64 .64 0 0 1 .7-.7 .64 .64 0 0 1 .6 .7 .64 .64 0 0 1 .6-.7 .64 .64 0 0 1 .7 .7 .64 .64 0 0 1 .6-.7 .64 .64 0 0 1 .6 .7 .64 .64 0 0 1 .7-.7 .64 .64 0 0 1 .6 .7h1.3M110.5 74.9v2.8M110.5 79.8v2.8M86.4 83.8v1.3h1.2l-1.2 1.3-1.3-1.3h1.3M86.4 83.8h.1M95.2 83.8v1.3h1.3l-1.3 1.3-1.2-1.3h1.2M95.2 83.8h.1M110.5 83.8v1.3h1.3l-1.3 1.3-1.3-1.3h1.3"/>
<path d="M110.5 83.8h.1M247.6 113h.1M247.6 110.5l-.7 1.3M247.6 110.5l.8 1.3M247.6 110.5v2.5M160 153.7v2.8M160 158.5v2.8M172.7 153.7v1.2M182.9 143.5h.1M182.9 141l-.8 1.2M182.9 141l.7 1.2M182.9 141v2.5"/>
<path d="M198.1 157.5v1.3h1.3l-1.3 1.2-1.3-1.2h1.3M198.1 157.5h.1M160 163.8v1.3h1.3l-1.3 1.3-1.3-1.3h1.3M160 163.8h.1M172.7 163.8v1.3h1.3l-1.3 1.3-1.3-1.3h1.3M172.7 163.8h.1M172.7 160v1.3"/>
</g>
<path d="M84.3 78h4.1M84.3 79.5h4.1M93.2 78h4.1M93.2 79.5h4.1M108.5 78h4M108.5 79.5h4M158 158.2h4.1M158 156.7h4.1" fill="none" stroke="#840000" stroke-width=".51"/>
<path d="M188 146.1h5v10.1h-5z" fill="#ffffc2"/>
<path d="M188 146.1h5v10.1h-5z" fill="none" stroke="#840000" stroke-width=".25"/>
<g fill="none" stroke="#840000" stroke-width=".15">
<path d="M53.3 39.4v1.2l1.1 .7-1.1 .6-1-.6 1-.7M53.3 39.4h.1M125.7 31.8v2.7M125.7 36.6v2.8M132.1 26.7h.1M132.1 24.1v2.6M132.1 31.8v2.7M132.1 36.6v2.8M132.1 24.1l-.8 1.3M132.1 24.1l.7 1.3M152.4 24.1h.1M152.4 21.6l-.8 1.3"/>
<path d="M152.4 21.6l.8 1.3M152.4 21.6v2.5M198.1 33h.1M198.1 30.5l-.7 1.3M198.1 30.5l.8 1.3M198.1 30.5v2.5M125.7 41.9v1.3h1.3l-1.3 1.3-1.2-1.3h1.2M125.7 41.9h.1M132.1 41.9v1.3h1.2l-1.2 1.3-1.3-1.3h1.3M132.1 41.9h.1M160 120.7h2.8M160 125.7h2.8"/>
<path d="M164.8 120.7h2.8M164.8 125.7h2.8M171.4 128.3v1.2h1.3l-1.3 1.3-1.2-1.3h1.2M171.4 128.3h.1M182.9 157.5v1.3h1.2l-1.2 1.2-1.3-1.2h1.3M182.9 157.5h.1M184.1 147.3h3.9M184.1 149.9h3.9M184.1 152.4h3.9M184.1 154.9h3.9M188 147.2h1.2v.2h-1.2zM188 149.7h1.2v.3h-1.2z"/>
<path d="M188 152.3h1.2v.2h-1.2zM188 154.8h1.2v.3h-1.2zM191.8 147.2h1.2v.2h-1.2zM191.8 149.7h1.2v.3h-1.2zM191.8 152.3h1.2v.2h-1.2zM191.8 154.8h1.2v.3h-1.2zM193 147.3h3.8M193 149.9h3.8M193 152.4h3.8M193 154.9h3.8"/>
</g>
<path d="M123.7 36.3h4.1M123.7 34.8h4.1M130 36.3h4.1M130 34.8h4.1M163.1 118.6v4.1M164.6 118.6v4.1M163.1 123.7v4.1M164.6 123.7v4.1" fill="none" stroke="#840000" stroke-width=".51"/>
<path d="M179.1 34.9h10.1v9.6h-10.1z" fill="#ffffc2"/>
<path d="M115.8 31.8h2.1v5h-2.1zM158.7 24.1l2.6 1.3-2.6 1.3zM160.7 24.8v-.7h.6v2.6h.6v-.7M179.1 34.9h10.1v9.6h-10.1zM115.8 41.9h2.1v5.1h-2.1z" fill="none" stroke="#840000" stroke-width=".25"/>
<g fill="none" stroke="#840000" stroke-width=".15">
<path d="M69.8 24.1h2.6M69.8 29.2h2.6M82.5 36.8v2.6M92.7 24.1h2.5M92.7 29.2h2.5M92.7 34.3h2.5M96.5 24.1h2.8M101.3 24.1h2.8M107.9 29.2h1.3a.64 .64 0 0 1 .7-.6 .64 .64 0 0 1 .6 .6 .64 .64 0 0 1 .6-.6 .64 .64 0 0 1 .7 .6 .64 .64 0 0 1 .6-.6 .64 .64 0 0 1 .6 .6 .64 .64 0 0 1 .7-.6 .64 .64 0 0 1 .6 .6h1.3M116.8 30.5v1.3M116.8 36.8v1.3M125.7 31.8v2.7"/>
<path d="M125.7 36.6v2.8M132.1 31.8v2.7M132.1 36.6v2.8M156.2 25.4h7.6M176.5 36.8h2.6M176.5 39.4h2.6M189.2 36.8h2.6M198.1 39.4v2.8M252.7 24.1h.1M255.3 25.4h3.8M255.3 27.9h3.8M255.3 30.5h3.8"/>
<path d="M255.3 33h3.8M255.3 35.6h3.8M116.8 40.6v1.3M116.8 47v1.3M184.1 44.5v2.5M198.1 44.2v2.8M43.2 62.2h5.1M43.2 67.3h5.1M43.2 74.9h5.1M43.2 69.9h5.1M43.2 77.5h5.1M52.1 67.3h1.2"/>
<path d="M52.1 69.9h1.2M58.4 67.3h1.3M58.4 69.9h1.3M25.4 95.3v5M33 95.3v5M43.2 80h5.1M43.2 90.2h5.1M43.2 82.6h5.1M43.2 92.7h5.1M33 102.9h.1M48.3 105.4h.1M48.3 108v1.2"/>
<path d="M48.3 114.3v3.8M55.9 108v1.2M55.9 114.3v3.8M63.5 108v1.2M63.5 114.3v3.8M116.8 115.6v2.5M121.9 115.6v2.5M127 115.6v2.5M132.1 115.6v2.5M137.2 115.6v2.5M142.2 110.5h.1M142.2 101.6v2.8"/>
<path d="M142.2 106.4v2.8M148.6 110.5h.1M148.6 101.6v2.8M148.6 106.4v2.8M214.6 119.4h5.1M222.2 114.3v2.5M48.3 120.7v2.5M55.9 120.7v2.5M63.5 120.7v2.5M104.1 120.7h2.6M104.1 125.7h2.6M104.1 123.2h2.6"/>
<path d="M104.1 130.8h2.6M104.1 133.4h2.6M104.1 135.9h2.6M104.1 128.3h2.6M147.3 120.7h2.6M147.3 125.7h2.6M147.3 130.8h2.6M147.3 133.4h2.6M147.3 135.9h2.6M147.3 138.4h2.6M160 120.7h2.8M160 125.7h2.8"/>
<path d="M164.8 120.7h2.8M164.8 125.7h2.8M214.6 132.1h5.1M222.2 138.4h.1M222.2 121.9v2.6M222.2 127v2.5M222.2 134.6v2.6M29.2 148.6h.1M38.1 151.1h2.5M43.2 151.1h2.5M48.3 142.2v1.3M48.3 148.6v1.3"/>
<path d="M55.9 142.2v1.3M55.9 148.6v1.3M63.5 142.2v1.3M63.5 148.6v1.3M71.1 142.2v1.3M71.1 148.6v1.3M104.1 148.6h2.6M104.1 151.1h2.6M104.1 143.5h2.6M104.1 153.7h2.6M104.1 156.2h2.6M104.1 141h2.6"/>
<path d="M147.3 148.6h2.6M147.3 151.1h2.6M147.3 143.5h2.6M147.3 146.1h2.6M147.3 153.7h2.6M147.3 156.2h2.6M182.9 143.5h.1M184.1 147.3h3.9M184.1 149.9h3.9M184.1 152.4h3.9M184.1 154.9h3.9M193 147.3h3.8"/>
<path d="M193 149.9h3.8M193 152.4h3.8M193 154.9h3.8M198.1 143.5h.1M87.6 162.6v2.8M87.6 167.4v2.8M90.2 161.3h1.2M94 165.1v1.3M96.5 161.3h1.3M100.3 162.6v2.8M100.3 167.4v2.8M127 167.6h.1"/>
<path d="M127 163.8v2.6"/>
</g>
<path d="M99.6 22.1v4.1M101.1 22.1v4.1M196.1 43.9h4.1M196.1 42.4h4.1" fill="none" stroke="#840000" stroke-width=".51"/>
<g fill="none" stroke="#009600" stroke-width=".15">
<path d="M43.2 36.8h20.3M43.2 21.6v5.1M43.2 34.3v5.1M43.2 24.1h26.6M53.3 21.6v5.1M53.3 34.3v5.1M63.5 24.1v2.6M63.5 34.3v5.1M67.3 24.1v5.1h2.5M82.5 39.4v2.5M95.2 24.1h1.3M95.2 34.3h11.5v5.1h10.1"/>
<path d="M95.2 29.2h12.7M104.1 24.1h2.6v5.1M115.6 29.2h16.5M116.8 29.2v1.3M116.8 38.1v2.5M125.7 29.2v2.6M125.7 39.4v2.5M132.1 26.7v5.1M132.1 39.4v2.5M152.4 36.8h3.8M152.4 24.1v1.3h3.8M163.8 36.8h12.7"/>
<path d="M163.8 25.4h3.8v14M175.3 36.8v2.6h1.2M191.8 36.8h6.3M198.1 33v6.4M248.9 27.9h6.4M252.7 24.1v1.3h2.6M252.7 35.6h2.6M252.7 33h2.6M252.7 30.5h2.6M116.8 48.3v1.2M167.6 47v2.5h30.5v-2.5M184.1 47v5.1"/>
<path d="M213.4 57.2h10.1M213.4 54.6v3.8M243.8 57.2h16.5M243.8 59.7h2.6M254 59.7h2.5v2.5h-12.7M268 57.2h5M48.3 69.9h3.8M48.3 74.9h3.8M48.3 67.3h3.8M48.3 62.2h1.2M49.5 74.9v2.6h-1.2M59.7 69.9h12.7"/>
<path d="M59.7 74.9h2.5M59.7 67.3h12.7v6.4M86.4 73.7h12.7M86.4 69.9v5M95.2 73.7v1.2M106.7 73.7h10.1v41.9M110.5 73.7v1.2M213.4 66v1.3M222.2 69.9h1.3M222.2 64.8h1.3M222.2 74.9h1.3M222.2 67.3h1.3"/>
<path d="M222.2 62.2h1.3M222.2 72.4h1.3M243.8 69.9h16.5M243.8 64.8h16.5M243.8 77.5h16.5M243.8 72.4h2.6M254 72.4h2.5v2.5h-12.7M256.5 73.7h16.5M256.5 61h16.5M268 69.9h5M268 64.8h5M268 77.5h5"/>
<path d="M48.3 82.6h3.8M48.3 80h1.2v2.6M59.7 82.6h2.5M86.4 82.6v1.2M95.2 82.6v1.2M110.5 82.6v1.2M127 85.1h1.3M127 80v35.6M132.1 99.1v2.5M135.9 85.1h2.5M148.6 97.8v3.8M213.4 90.2v2.5"/>
<path d="M222.2 90.2h1.3M223.5 87.6h-1.3v5.1M223.5 80h-10.1v2.6M243.8 90.2h16.5M243.8 82.6h16.5M243.8 85.1h2.6M254 85.1h2.5v2.5h-12.7M256.5 86.4h16.5M268 90.2h5M268 82.6h5M25.4 100.3h7.6v2.6M48.3 106.7h22.8v1.3"/>
<path d="M48.3 105.4v2.6M55.9 106.7v1.3M63.5 106.7v1.3M82.5 106.7h15.3v1.3M82.5 105.4v2.6M82.5 115.6v12.7h21.6M90.2 115.6v10.1h13.9M90.2 106.7v1.3M97.8 115.6v5.1h6.3M127 113h-5.1v2.6M132.1 109.2v6.4M142.2 100.3v1.3"/>
<path d="M142.2 109.2v1.3M148.6 109.2v1.3M148.6 100.3h-11.4v15.3M154.9 105.4v2.6M154.9 115.6v10.1M167.6 109.2v-2.5h15.3v3.8M171.4 106.7v14h-3.8M213.4 119.4h1.2M222.2 113v1.3M238.8 119.4h1.2M247.6 113v1.3M262.9 119.4h1.3"/>
<path d="M271.8 113v1.3M31.7 137.2v6.3h-6.3M48.3 123.2v2.5M48.3 137.2v5M55.9 123.2v2.5M63.5 123.2v2.5M102.9 135.9h1.2M102.9 130.8h1.2M102.9 133.4h1.2M102.9 123.2h1.2M149.9 125.7h10.1M149.9 120.7h10.1"/>
<path d="M149.9 135.9h1.2M149.9 130.8h1.2M149.9 133.4h1.2M149.9 138.4h1.2M167.6 125.7h3.8v2.6M213.4 125.7h8.8M213.4 132.1h1.2M222.2 124.5v2.5M222.2 137.2v1.2M238.8 125.7h8.8M238.8 132.1h1.2M247.6 124.5v2.5"/>
<path d="M247.6 137.2v1.2M262.9 125.7h8.9M262.9 132.1h1.3M271.8 124.5v2.5M271.8 137.2v1.2M25.4 153.7h8.9v7.6h3.8M25.4 156.2h6.3v15.3h6.4M25.4 151.1h12.7M25.4 148.6h3.8M45.7 151.1h28M48.3 149.9v24.1M55.9 141v1.2"/>
<path d="M55.9 149.9v24.1M63.5 141v1.2M63.5 149.9v24.1M71.1 142.2v-1.2h-36.8v5.1h-8.9M71.1 149.9v24.1M102.9 151.1h1.2M102.9 141h1.2M102.9 148.6h1.2M102.9 143.5h1.2M104.1 153.7h-16.5v8.9M104.1 156.2h-3.8v6.4M162.6 149.9h-2.6v3.8"/>
<path d="M170.2 149.9h13.9M172.7 149.9v3.8M181.6 154.9h2.5M182.9 143.5v3.8h1.2M184.1 152.4h-1.2v5.1M196.8 152.4h1.3v5.1M196.8 149.9h2.6M196.8 154.9h2.6M198.1 143.5v3.8h-1.3M45.7 161.3h28M45.7 171.5h28M87.6 161.3h2.6"/>
<path d="M87.6 170.2v1.3h12.7v-1.3M94 166.4v7.6M97.8 161.3h2.5M127 166.4v1.2M160 161.3v2.5M172.7 161.3v2.5M48.3 181.6v1.3M55.9 181.6v1.3M63.5 181.6v1.3M71.1 181.6v1.3"/>
</g>
<g fill="none" stroke="#000084" stroke-width=".15">
<path d="M47.7 92.1l1.2 1.2M47.7 89.6l1.2 1.2M48.9 92.1l-1.2 1.2M48.9 89.6l-1.2 1.2M222.9 81.9l1.2 1.3M224.1 81.9l-1.2 1.3M70.5 115l1.2 1.2M71.7 115l-1.2 1.2M182.3 109.9l1.2 1.2M183.5 109.9l-1.2 1.2M149.3 148l1.2 1.2M149.3 155.6l1.2 1.2"/>
<path d="M149.3 150.5l1.2 1.2M149.3 153.1l1.2 1.2M149.3 145.4l1.2 1.3M149.3 142.9l1.2 1.2M150.5 142.9l-1.2 1.2M150.5 148l-1.2 1.2M150.5 155.6l-1.2 1.2M150.5 150.5l-1.2 1.2M150.5 153.1l-1.2 1.2M150.5 145.4l-1.2 1.3"/>
</g>
<g fill="#009600" stroke="#009600" stroke-width=".13">
<circle cx="222.2" cy="90.2" r=".46"/>
<circle cx="213.4" cy="57.2" r=".46"/>
<circle cx="256.5" cy="73.7" r=".46"/>
<circle cx="172.7" cy="149.9" r=".46"/>
<circle cx="222.2" cy="125.7" r=".46"/>
<circle cx="171.4" cy="106.7" r=".46"/>
<circle cx="198.1" cy="36.8" r=".46"/>
<circle cx="184.1" cy="49.5" r=".46"/>
<circle cx="175.3" cy="36.8" r=".46"/>
<circle cx="167.6" cy="36.8" r=".46"/>
<circle cx="256.5" cy="86.4" r=".46"/>
<circle cx="256.5" cy="61" r=".46"/>
<circle cx="247.6" cy="125.7" r=".46"/>
<circle cx="271.8" cy="125.7" r=".46"/>
<circle cx="49.5" cy="82.6" r=".46"/>
<circle cx="49.5" cy="74.9" r=".46"/>
<circle cx="33" cy="100.3" r=".46"/>
<circle cx="55.9" cy="106.7" r=".46"/>
<circle cx="48.3" cy="106.7" r=".46"/>
<circle cx="154.9" cy="125.7" r=".46"/>
<circle cx="148.6" cy="100.3" r=".46"/>
<circle cx="142.2" cy="100.3" r=".46"/>
<circle cx="127" cy="113" r=".46"/>
<circle cx="127" cy="85.1" r=".46"/>
<circle cx="43.2" cy="24.1" r=".46"/>
<circle cx="63.5" cy="24.1" r=".46"/>
<circle cx="67.3" cy="24.1" r=".46"/>
<circle cx="53.3" cy="24.1" r=".46"/>
<circle cx="43.2" cy="36.8" r=".46"/>
<circle cx="125.7" cy="29.2" r=".46"/>
<circle cx="132.1" cy="29.2" r=".46"/>
<circle cx="116.8" cy="39.4" r=".46"/>
<circle cx="116.8" cy="29.2" r=".46"/>
<circle cx="106.7" cy="29.2" r=".46"/>
<circle cx="53.3" cy="36.8" r=".46"/>
<circle cx="63.5" cy="36.8" r=".46"/>
<circle cx="72.4" cy="69.9" r=".46"/>
<circle cx="86.4" cy="73.7" r=".46"/>
<circle cx="110.5" cy="73.7" r=".46"/>
<circle cx="95.2" cy="73.7" r=".46"/>
<circle cx="63.5" cy="171.5" r=".46"/>
<circle cx="55.9" cy="161.3" r=".46"/>
<circle cx="90.2" cy="106.7" r=".46"/>
<circle cx="82.5" cy="106.7" r=".46"/>
<circle cx="55.9" cy="141" r=".46"/>
<circle cx="63.5" cy="141" r=".46"/>
<circle cx="63.5" cy="106.7" r=".46"/>
<circle cx="87.6" cy="161.3" r=".46"/>
<circle cx="100.3" cy="161.3" r=".46"/>
<circle cx="94" cy="171.5" r=".46"/>
<circle cx="48.3" cy="141" r=".46"/>
<circle cx="48.3" cy="151.1" r=".46"/>
</g>
<use href="#words"/>
</svg>
